###############################################################
#  Generated by:      Cadence Innovus 21.13-s100_1
#  OS:                Linux x86_64(Host ID tajumulco.ee.ethz.ch)
#  Generated on:      Thu Sep  3 16:09:14 2026
#  Design:            tt_um_ez130_8t_mystery
#  Command:           write_lef_abstract -stripePin -PGPinLayers TopMetal1 -specifyTopLayer TopMetal1 ./out/RegMult.lef
###############################################################

VERSION 5.8 ;

BUSBITCHARS "[]" ;
DIVIDERCHAR "/" ;

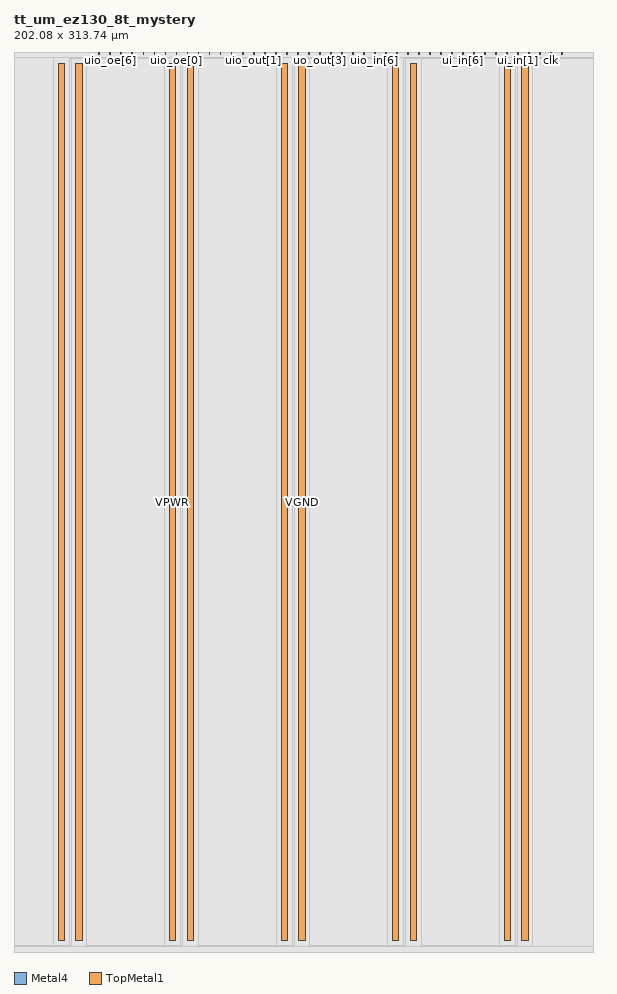
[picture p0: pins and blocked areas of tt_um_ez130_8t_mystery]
MACRO tt_um_ez130_8t_mystery
  CLASS BLOCK ;
  SIZE 202.080000 BY 313.740000 ;
  FOREIGN tt_um_ez130_8t_mystery 0.000000 0.000000 ;
  ORIGIN 0 0 ;
  SYMMETRY X Y R90 ;
  PIN ui_in[7]
    DIRECTION INPUT ;
    USE SIGNAL ;
    PORT
      LAYER Metal4 ;
        RECT 152.490000 312.740000 152.790000 313.740000 ;
    END
  END ui_in[7]
  PIN ui_in[6]
    DIRECTION INPUT ;
    USE SIGNAL ;
    PORT
      LAYER Metal4 ;
        RECT 156.330000 312.740000 156.630000 313.740000 ;
    END
  END ui_in[6]
  PIN ui_in[5]
    DIRECTION INPUT ;
    USE SIGNAL ;
    PORT
      LAYER Metal4 ;
        RECT 160.170000 312.740000 160.470000 313.740000 ;
    END
  END ui_in[5]
  PIN ui_in[4]
    DIRECTION INPUT ;
    USE SIGNAL ;
    PORT
      LAYER Metal4 ;
        RECT 164.010000 312.740000 164.310000 313.740000 ;
    END
  END ui_in[4]
  PIN ui_in[3]
    DIRECTION INPUT ;
    USE SIGNAL ;
    PORT
      LAYER Metal4 ;
        RECT 167.850000 312.740000 168.150000 313.740000 ;
    END
  END ui_in[3]
  PIN ui_in[2]
    DIRECTION INPUT ;
    USE SIGNAL ;
    PORT
      LAYER Metal4 ;
        RECT 171.690000 312.740000 171.990000 313.740000 ;
    END
  END ui_in[2]
  PIN ui_in[1]
    DIRECTION INPUT ;
    USE SIGNAL ;
    PORT
      LAYER Metal4 ;
        RECT 175.530000 312.740000 175.830000 313.740000 ;
    END
  END ui_in[1]
  PIN ui_in[0]
    DIRECTION INPUT ;
    USE SIGNAL ;
    PORT
      LAYER Metal4 ;
        RECT 179.370000 312.740000 179.670000 313.740000 ;
    END
  END ui_in[0]
  PIN uo_out[7]
    DIRECTION OUTPUT ;
    USE SIGNAL ;
    PORT
      LAYER Metal4 ;
        RECT 91.050000 312.740000 91.350000 313.740000 ;
    END
  END uo_out[7]
  PIN uo_out[6]
    DIRECTION OUTPUT ;
    USE SIGNAL ;
    PORT
      LAYER Metal4 ;
        RECT 94.890000 312.740000 95.190000 313.740000 ;
    END
  END uo_out[6]
  PIN uo_out[5]
    DIRECTION OUTPUT ;
    USE SIGNAL ;
    PORT
      LAYER Metal4 ;
        RECT 98.730000 312.740000 99.030000 313.740000 ;
    END
  END uo_out[5]
  PIN uo_out[4]
    DIRECTION OUTPUT ;
    USE SIGNAL ;
    PORT
      LAYER Metal4 ;
        RECT 102.570000 312.740000 102.870000 313.740000 ;
    END
  END uo_out[4]
  PIN uo_out[3]
    DIRECTION OUTPUT ;
    USE SIGNAL ;
    PORT
      LAYER Metal4 ;
        RECT 106.410000 312.740000 106.710000 313.740000 ;
    END
  END uo_out[3]
  PIN uo_out[2]
    DIRECTION OUTPUT ;
    USE SIGNAL ;
    PORT
      LAYER Metal4 ;
        RECT 110.250000 312.740000 110.550000 313.740000 ;
    END
  END uo_out[2]
  PIN uo_out[1]
    DIRECTION OUTPUT ;
    USE SIGNAL ;
    PORT
      LAYER Metal4 ;
        RECT 114.090000 312.740000 114.390000 313.740000 ;
    END
  END uo_out[1]
  PIN uo_out[0]
    DIRECTION OUTPUT ;
    USE SIGNAL ;
    PORT
      LAYER Metal4 ;
        RECT 117.930000 312.740000 118.230000 313.740000 ;
    END
  END uo_out[0]
  PIN uio_in[7]
    DIRECTION INPUT ;
    USE SIGNAL ;
    PORT
      LAYER Metal4 ;
        RECT 121.770000 312.740000 122.070000 313.740000 ;
    END
  END uio_in[7]
  PIN uio_in[6]
    DIRECTION INPUT ;
    USE SIGNAL ;
    PORT
      LAYER Metal4 ;
        RECT 125.610000 312.740000 125.910000 313.740000 ;
    END
  END uio_in[6]
  PIN uio_in[5]
    DIRECTION INPUT ;
    USE SIGNAL ;
    PORT
      LAYER Metal4 ;
        RECT 129.450000 312.740000 129.750000 313.740000 ;
    END
  END uio_in[5]
  PIN uio_in[4]
    DIRECTION INPUT ;
    USE SIGNAL ;
    PORT
      LAYER Metal4 ;
        RECT 133.290000 312.740000 133.590000 313.740000 ;
    END
  END uio_in[4]
  PIN uio_in[3]
    DIRECTION INPUT ;
    USE SIGNAL ;
    PORT
      LAYER Metal4 ;
        RECT 137.130000 312.740000 137.430000 313.740000 ;
    END
  END uio_in[3]
  PIN uio_in[2]
    DIRECTION INPUT ;
    USE SIGNAL ;
    PORT
      LAYER Metal4 ;
        RECT 140.970000 312.740000 141.270000 313.740000 ;
    END
  END uio_in[2]
  PIN uio_in[1]
    DIRECTION INPUT ;
    USE SIGNAL ;
    PORT
      LAYER Metal4 ;
        RECT 144.810000 312.740000 145.110000 313.740000 ;
    END
  END uio_in[1]
  PIN uio_in[0]
    DIRECTION INPUT ;
    USE SIGNAL ;
    PORT
      LAYER Metal4 ;
        RECT 148.650000 312.740000 148.950000 313.740000 ;
    END
  END uio_in[0]
  PIN uio_out[7]
    DIRECTION OUTPUT ;
    USE SIGNAL ;
    PORT
      LAYER Metal4 ;
        RECT 60.330000 312.740000 60.630000 313.740000 ;
    END
  END uio_out[7]
  PIN uio_out[6]
    DIRECTION OUTPUT ;
    USE SIGNAL ;
    PORT
      LAYER Metal4 ;
        RECT 64.170000 312.740000 64.470000 313.740000 ;
    END
  END uio_out[6]
  PIN uio_out[5]
    DIRECTION OUTPUT ;
    USE SIGNAL ;
    PORT
      LAYER Metal4 ;
        RECT 68.010000 312.740000 68.310000 313.740000 ;
    END
  END uio_out[5]
  PIN uio_out[4]
    DIRECTION OUTPUT ;
    USE SIGNAL ;
    PORT
      LAYER Metal4 ;
        RECT 71.850000 312.740000 72.150000 313.740000 ;
    END
  END uio_out[4]
  PIN uio_out[3]
    DIRECTION OUTPUT ;
    USE SIGNAL ;
    PORT
      LAYER Metal4 ;
        RECT 75.690000 312.740000 75.990000 313.740000 ;
    END
  END uio_out[3]
  PIN uio_out[2]
    DIRECTION OUTPUT ;
    USE SIGNAL ;
    PORT
      LAYER Metal4 ;
        RECT 79.530000 312.740000 79.830000 313.740000 ;
    END
  END uio_out[2]
  PIN uio_out[1]
    DIRECTION OUTPUT ;
    USE SIGNAL ;
    PORT
      LAYER Metal4 ;
        RECT 83.370000 312.740000 83.670000 313.740000 ;
    END
  END uio_out[1]
  PIN uio_out[0]
    DIRECTION OUTPUT ;
    USE SIGNAL ;
    PORT
      LAYER Metal4 ;
        RECT 87.210000 312.740000 87.510000 313.740000 ;
    END
  END uio_out[0]
  PIN uio_oe[7]
    DIRECTION OUTPUT ;
    USE SIGNAL ;
    PORT
      LAYER Metal4 ;
        RECT 29.610000 312.740000 29.910000 313.740000 ;
    END
  END uio_oe[7]
  PIN uio_oe[6]
    DIRECTION OUTPUT ;
    USE SIGNAL ;
    PORT
      LAYER Metal4 ;
        RECT 33.450000 312.740000 33.750000 313.740000 ;
    END
  END uio_oe[6]
  PIN uio_oe[5]
    DIRECTION OUTPUT ;
    USE SIGNAL ;
    PORT
      LAYER Metal4 ;
        RECT 37.290000 312.740000 37.590000 313.740000 ;
    END
  END uio_oe[5]
  PIN uio_oe[4]
    DIRECTION OUTPUT ;
    USE SIGNAL ;
    PORT
      LAYER Metal4 ;
        RECT 41.130000 312.740000 41.430000 313.740000 ;
    END
  END uio_oe[4]
  PIN uio_oe[3]
    DIRECTION OUTPUT ;
    USE SIGNAL ;
    PORT
      LAYER Metal4 ;
        RECT 44.970000 312.740000 45.270000 313.740000 ;
    END
  END uio_oe[3]
  PIN uio_oe[2]
    DIRECTION OUTPUT ;
    USE SIGNAL ;
    PORT
      LAYER Metal4 ;
        RECT 48.810000 312.740000 49.110000 313.740000 ;
    END
  END uio_oe[2]
  PIN uio_oe[1]
    DIRECTION OUTPUT ;
    USE SIGNAL ;
    PORT
      LAYER Metal4 ;
        RECT 52.650000 312.740000 52.950000 313.740000 ;
    END
  END uio_oe[1]
  PIN uio_oe[0]
    DIRECTION OUTPUT ;
    USE SIGNAL ;
    PORT
      LAYER Metal4 ;
        RECT 56.490000 312.740000 56.790000 313.740000 ;
    END
  END uio_oe[0]
  PIN ena
    DIRECTION INPUT ;
    USE SIGNAL ;
    PORT
      LAYER Metal4 ;
        RECT 190.890000 312.740000 191.190000 313.740000 ;
    END
  END ena
  PIN clk
    DIRECTION INPUT ;
    USE SIGNAL ;
    PORT
      LAYER Metal4 ;
        RECT 187.050000 312.740000 187.350000 313.740000 ;
    END
  END clk
  PIN rst_n
    DIRECTION INPUT ;
    USE SIGNAL ;
    PORT
      LAYER Metal4 ;
        RECT 183.210000 312.740000 183.510000 313.740000 ;
    END
  END rst_n
  PIN VPWR
    DIRECTION INOUT ;
    USE POWER ;

# P/G power stripe data as pin
    PORT
      LAYER TopMetal1 ;
        RECT 170.860000 3.990000 173.060000 309.750000 ;
        RECT 131.990000 3.990000 134.190000 309.750000 ;
        RECT 93.120000 3.990000 95.320000 309.750000 ;
        RECT 54.250000 3.990000 56.450000 309.750000 ;
        RECT 15.380000 3.990000 17.580000 309.750000 ;
    END
# end of P/G power stripe data as pin

  END VPWR
  PIN VGND
    DIRECTION INOUT ;
    USE GROUND ;

# P/G power stripe data as pin
    PORT
      LAYER TopMetal1 ;
        RECT 177.060000 3.990000 179.260000 309.750000 ;
        RECT 138.190000 3.990000 140.390000 309.750000 ;
        RECT 99.320000 3.990000 101.520000 309.750000 ;
        RECT 60.450000 3.990000 62.650000 309.750000 ;
        RECT 21.580000 3.990000 23.780000 309.750000 ;
    END
# end of P/G power stripe data as pin

  END VGND
  OBS
    LAYER Metal1 ;
      RECT 0.000000 0.000000 202.080000 313.740000 ;
    LAYER Metal2 ;
      RECT 0.000000 0.000000 202.080000 313.740000 ;
    LAYER Metal3 ;
      RECT 0.000000 0.000000 202.080000 313.740000 ;
    LAYER Metal4 ;
      RECT 191.400000 312.530000 202.080000 313.740000 ;
      RECT 187.560000 312.530000 190.680000 313.740000 ;
      RECT 183.720000 312.530000 186.840000 313.740000 ;
      RECT 179.880000 312.530000 183.000000 313.740000 ;
      RECT 176.040000 312.530000 179.160000 313.740000 ;
      RECT 172.200000 312.530000 175.320000 313.740000 ;
      RECT 168.360000 312.530000 171.480000 313.740000 ;
      RECT 164.520000 312.530000 167.640000 313.740000 ;
      RECT 160.680000 312.530000 163.800000 313.740000 ;
      RECT 156.840000 312.530000 159.960000 313.740000 ;
      RECT 153.000000 312.530000 156.120000 313.740000 ;
      RECT 149.160000 312.530000 152.280000 313.740000 ;
      RECT 145.320000 312.530000 148.440000 313.740000 ;
      RECT 141.480000 312.530000 144.600000 313.740000 ;
      RECT 137.640000 312.530000 140.760000 313.740000 ;
      RECT 133.800000 312.530000 136.920000 313.740000 ;
      RECT 129.960000 312.530000 133.080000 313.740000 ;
      RECT 126.120000 312.530000 129.240000 313.740000 ;
      RECT 122.280000 312.530000 125.400000 313.740000 ;
      RECT 118.440000 312.530000 121.560000 313.740000 ;
      RECT 114.600000 312.530000 117.720000 313.740000 ;
      RECT 110.760000 312.530000 113.880000 313.740000 ;
      RECT 106.920000 312.530000 110.040000 313.740000 ;
      RECT 103.080000 312.530000 106.200000 313.740000 ;
      RECT 99.240000 312.530000 102.360000 313.740000 ;
      RECT 95.400000 312.530000 98.520000 313.740000 ;
      RECT 91.560000 312.530000 94.680000 313.740000 ;
      RECT 87.720000 312.530000 90.840000 313.740000 ;
      RECT 83.880000 312.530000 87.000000 313.740000 ;
      RECT 80.040000 312.530000 83.160000 313.740000 ;
      RECT 76.200000 312.530000 79.320000 313.740000 ;
      RECT 72.360000 312.530000 75.480000 313.740000 ;
      RECT 68.520000 312.530000 71.640000 313.740000 ;
      RECT 64.680000 312.530000 67.800000 313.740000 ;
      RECT 60.840000 312.530000 63.960000 313.740000 ;
      RECT 57.000000 312.530000 60.120000 313.740000 ;
      RECT 53.160000 312.530000 56.280000 313.740000 ;
      RECT 49.320000 312.530000 52.440000 313.740000 ;
      RECT 45.480000 312.530000 48.600000 313.740000 ;
      RECT 41.640000 312.530000 44.760000 313.740000 ;
      RECT 37.800000 312.530000 40.920000 313.740000 ;
      RECT 33.960000 312.530000 37.080000 313.740000 ;
      RECT 30.120000 312.530000 33.240000 313.740000 ;
      RECT 0.000000 312.530000 29.400000 313.740000 ;
      RECT 0.000000 0.000000 202.080000 312.530000 ;
    LAYER Metal5 ;
      RECT 0.000000 0.000000 202.080000 313.740000 ;
    LAYER TopMetal1 ;
      RECT 0.000000 311.940000 202.080000 313.740000 ;
      RECT 174.700000 311.390000 202.080000 311.940000 ;
      RECT 135.830000 311.390000 169.220000 311.940000 ;
      RECT 96.960000 311.390000 130.350000 311.940000 ;
      RECT 58.090000 311.390000 91.480000 311.940000 ;
      RECT 19.220000 311.390000 52.610000 311.940000 ;
      RECT 174.700000 2.350000 175.420000 311.390000 ;
      RECT 142.030000 2.350000 169.220000 311.390000 ;
      RECT 135.830000 2.350000 136.550000 311.390000 ;
      RECT 103.160000 2.350000 130.350000 311.390000 ;
      RECT 96.960000 2.350000 97.680000 311.390000 ;
      RECT 64.290000 2.350000 91.480000 311.390000 ;
      RECT 58.090000 2.350000 58.810000 311.390000 ;
      RECT 25.420000 2.350000 52.610000 311.390000 ;
      RECT 19.220000 2.350000 19.940000 311.390000 ;
      RECT 0.000000 2.350000 13.740000 311.940000 ;
      RECT 180.900000 1.800000 202.080000 311.390000 ;
      RECT 142.030000 1.800000 175.420000 2.350000 ;
      RECT 103.160000 1.800000 136.550000 2.350000 ;
      RECT 64.290000 1.800000 97.680000 2.350000 ;
      RECT 25.420000 1.800000 58.810000 2.350000 ;
      RECT 0.000000 1.800000 19.940000 2.350000 ;
      RECT 0.000000 0.000000 202.080000 1.800000 ;
  END
END tt_um_ez130_8t_mystery

END LIBRARY
